VERSION 5.7 ;
  NOWIREEXTENSIONATPIN ON ;
  DIVIDERCHAR "/" ;
  BUSBITCHARS "[]" ;
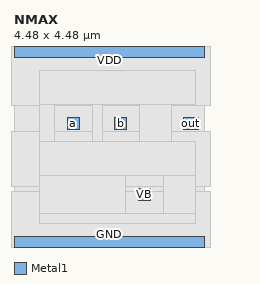
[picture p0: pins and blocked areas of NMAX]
MACRO NMAX
  CLASS CORE ;
  FOREIGN NMAX ;
  ORIGIN 0.000 0.000 ;
  SIZE 4.480 BY 4.480 ;
  SITE site056um ;
  PIN a
    ANTENNAGATEAREA 0.453200 ;
    PORT
      LAYER Metal1 ;
        RECT 1.260 2.660 1.540 2.940 ;
    END
  END a
  PIN b
    ANTENNAGATEAREA 0.453200 ;
    PORT
      LAYER Metal1 ;
        RECT 2.380 2.660 2.660 2.940 ;
    END
  END b
  PIN out
    ANTENNAGATEAREA 0.246400 ;
    ANTENNADIFFAREA 0.522800 ;
    PORT
      LAYER Metal1 ;
        RECT 4.005 2.660 4.340 2.940 ;
    END
  END out
  PIN VB
    ANTENNAGATEAREA 0.246400 ;
    PORT
      LAYER Metal1 ;
        RECT 2.940 0.980 3.220 1.260 ;
    END
  END VB
  PIN VDD
    USE POWER ;
    PORT
      LAYER Metal1 ;
        RECT 0.000 4.340 4.480 4.620 ;
    END
  END VDD
  PIN GND
    ANTENNADIFFAREA 0.151600 ;
    PORT
      LAYER Metal1 ;
        RECT 0.000 -0.140 4.480 0.140 ;
    END
  END GND
  OBS
      LAYER Nwell ;
        RECT -0.060 3.210 4.900 4.805 ;
        RECT 0.000 2.610 4.480 3.210 ;
        RECT -0.060 1.310 4.900 2.610 ;
        RECT 0.000 1.185 4.480 1.310 ;
      LAYER Pwell ;
        RECT -0.060 -0.140 4.900 1.185 ;
      LAYER Metal1 ;
        RECT 0.605 3.240 4.290 4.040 ;
        RECT 0.605 2.360 0.960 3.240 ;
        RECT 1.840 2.360 2.080 3.240 ;
        RECT 2.960 2.360 3.705 3.240 ;
        RECT 0.605 1.560 4.290 2.360 ;
        RECT 0.605 0.680 2.640 1.560 ;
        RECT 3.520 0.680 4.290 1.560 ;
        RECT 0.605 0.440 4.290 0.680 ;
  END
END NMAX
END LIBRARY

